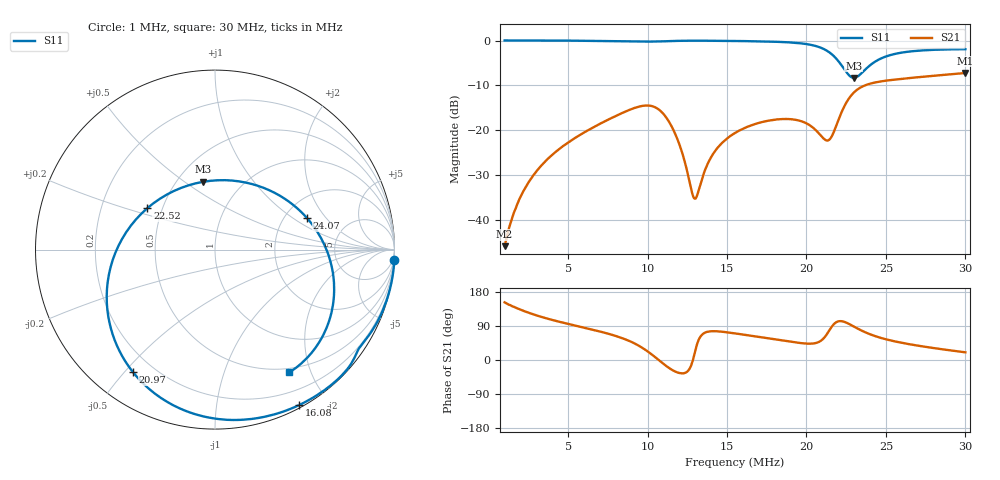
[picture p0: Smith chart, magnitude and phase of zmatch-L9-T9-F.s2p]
# HZ S RI R 50
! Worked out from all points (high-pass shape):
!   505 points, 1 MHz to 30 MHz, reference 50 ohm
!   highest |S21| = -7.25 dB at 30 MHz (marker M1); lowest = -45.9 dB at 1 MHz (marker M2)
!   |S21| within 3 dB of the highest: 23.53 MHz to end of sweep
!   lowest |S11| = -8.3 dB at 22.98 MHz (marker M3), VSWR 2.24, Z = 33.4 + j29.6 ohm
!   |S11| at or under -10 dB: nowhere
!   S12 and S22 are empty: the file has one direction only
!   S11 on the Smith chart (normalised r, x): 1 MHz: -1, -33; 16.08 MHz: 0.03, -1.68; 20.97 MHz: 0.13, -0.53; 22.52 MHz: 0.41, +0.24; 24.07 MHz: 2.63, +1.31; 30 MHz: 0.44, -1.69
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1000000  0.9993 -0.0606  -0.0045 0.00238  0 0  0 0
1805560  0.9951 -0.1075  -0.011 0.0104  0 0  0 0
2726200  0.9871 -0.161  -0.0157 0.0254  0 0  0 0
5833360  0.9354 -0.3376  0.00472 0.0905  0 0  0 0
9228220  0.834 -0.5079  0.131 0.1207  0 0  0 0
1.066672e7  0.7924 -0.5688  0.1719 0.00269  0 0  0 0
1.181752e7  0.7583 -0.6366  0.0715 -0.0445  0 0  0 0
1.296832e7  0.7002 -0.7072  0.0163 0.00563  0 0  0 0
1.406158e7  0.631 -0.7673  0.0127 0.0508  0 0  0 0
1.550008e7  0.5216 -0.839  0.0315 0.0876  0 0  0 0
1.607548e7  0.4697 -0.8656  0.0417 0.0966  0 0  0 0
1.849216e7  0.1636 -0.9473  0.0832 0.1041  0 0  0 0
2.033344e7  -0.2643 -0.8496  0.0795 0.075  0 0  0 0
2.096638e7  -0.4561 -0.6836  0.0512 0.067  0 0  0 0
2.14267e7  -0.5703 -0.472  0.0169 0.0764  0 0  0 0
2.182948e7  -0.6018 -0.2189  -0.0159 0.1059  0 0  0 0
2.251996e7  -0.377 0.2307  -0.0297 0.2029  0 0  0 0
2.298028e7  -0.0653 0.3778  0.00772 0.2628  0 0  0 0
2.407354e7  0.5127 0.1755  0.1314 0.3057  0 0  0 0
2.51668e7  0.6605 -0.1567  0.2169 0.287  0 0  0 0
2.712316e7  0.5949 -0.4918  0.3121 0.2359  0 0  0 0
3.000016e7  0.4147 -0.684  0.4075 0.1502  0 0  0 0
